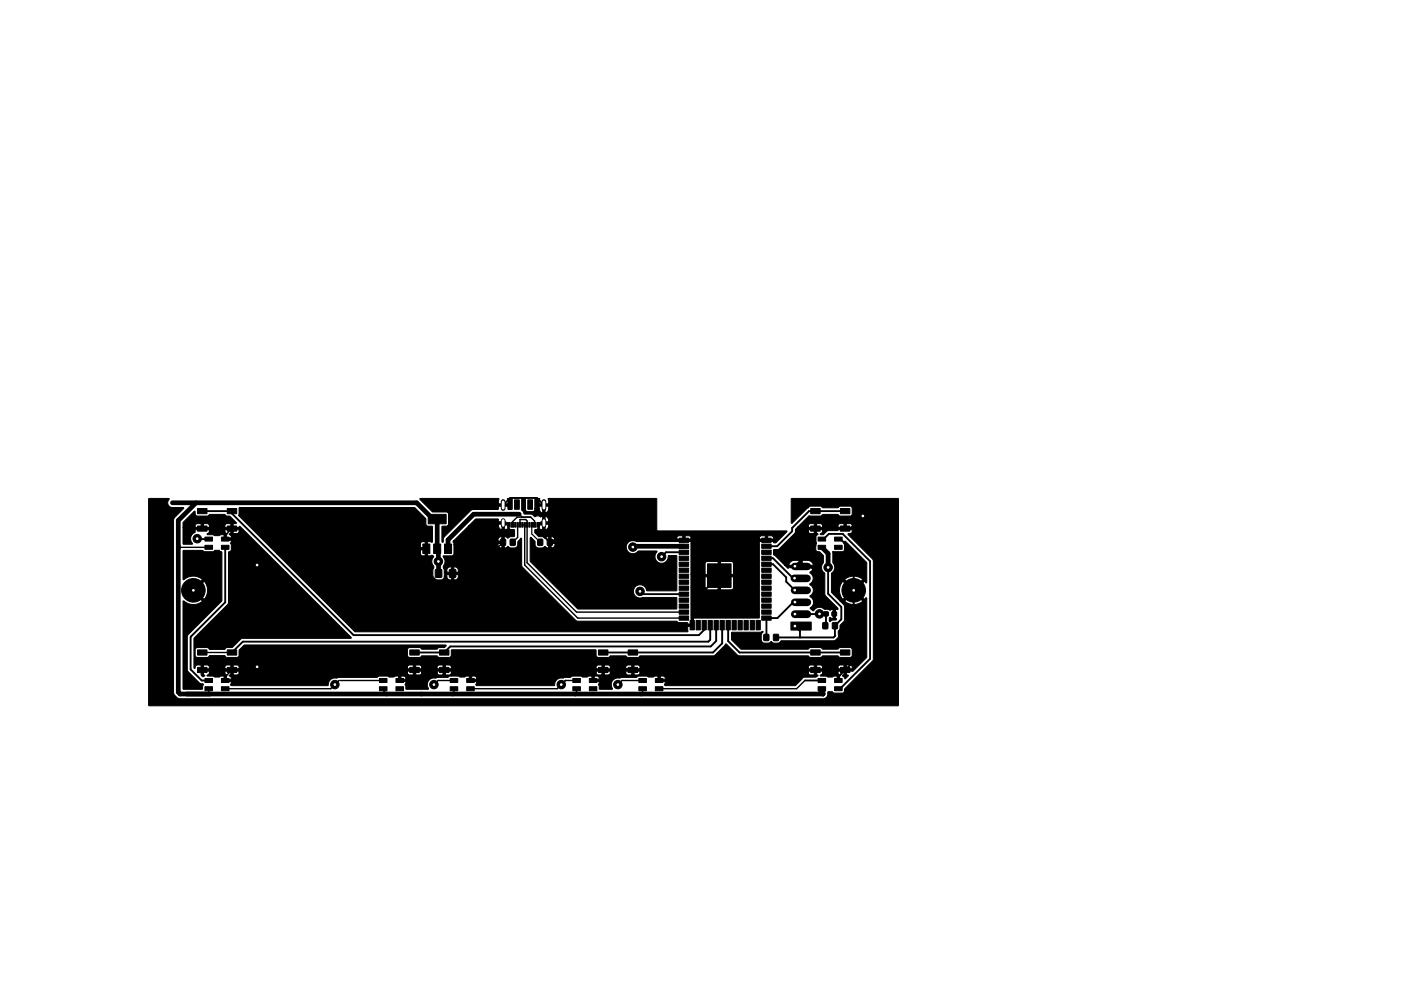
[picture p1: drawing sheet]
<svg xmlns="http://www.w3.org/2000/svg" width="297mm" height="210mm" viewBox="0 0 297 210" stroke-linecap="round" stroke-linejoin="round" font-family="sans-serif">
<g fill="#000" stroke="#000" stroke-width=".21">
<path d="M31.5 105.8l4.3-.1 .1 .2a1.03 1.03 0 0 0-.3 1.1 1.03 1.03 0 0 0 .9 .7h2.3l.2 .1-2 2-.2 .7v36.4l.3 .7 .5 .5 .5 .1h136.6l.7-.4 .2-1 .8-.1 .5 .3h1.7l.3-.1 .2-.7 6-6.2 .1-21-.2-.4-5.2-5.2v-.2l.8-.1 .1-.7h-3l-.1 .2h-2l-1 .8h-.6l-.1-.1 .4-.3 .1-.6h-1.2l-.1 .8 .3 .2-.4 .4v1.1l.1 .3-.1 .4v1.1l.2 .3 .6 .1 .8 .8v1.5l-.2 .2a1.42 1.42 0 0 0 .5 2v4.5l2.8 3-.1 .2h-.5v1.9l.3 .2-1.5 .5v-.9l.7 .2v-1.9l-.6 .2-.4-.2-.9-.1a1.47 1.47 0 0 0-2.3 .4l-.6-.6a1.41 1.41 0 0 0 .2-2.2l-.3-.3a1.44 1.44 0 0 0 0-2.5 1.45 1.45 0 0 0 0-2.5l.5-.5 .3-.6h-5.3l-.2 .2-.6-.7h6.1a1.25 1.25 0 0 0-1.2-1h-1.2v1h-.5v-1h-1.2l-.8 .3-.4 .7h-.8l-2.4-2.2v-1.1l1.2-.2 3.3-3.2 .2-.5h2.7l.4 .5h.8v-.8h-1.2v.3h-2.7v-.4l.4-.4h11.6l-.1-.6-.4-.2h-.8v.8h-.5v-.8l-1 .1-.2 .3v.4h-3.3l-.1-.6-.4-.2h-.8v.8h-.5v-.8l-1 .1-.2 .3v.4h-2.3l2.5-2.5 2.3 .1 .5-.4h3.2l.5 .4h2.2l.4-.4v-1.3l-.5-.4h-2.1l-.5 .3h-3.1l-.5-.3h-2.2l-.7 .5-3.3 3.1v-5.2h22.7l-.1 43.9h-158.8l-.1-.1zM41.2 108.5l.2 .1v.6l.4 .3h2.2l.4-.4h3.2l.5 .4h.6l1.4 1.4-.1 .2h-.6v.8h1.3v-.2h.2l23.6 23.6-.1 .1h-23l-.4 .2-1.7 1.8h-1.2l-.5 .4h-3.1l-.6-.4h-2.3l-.2 .4v1.2l.4 .5h2.2l.5-.4h3.1l.5 .4h2.2l.4-.4v-1.2l1.1-1.1 42.8 .1-.4 .5h-1.1l-.5 .3h-3.1l-.5-.3h-2.2l-.4 .4v1.2l.1 .3 .3 .2h2.2l.5-.4h3.1l.5 .4h2.2l.4-.4v-1.1l.1-.1h30.5l.1 .1v1.1l.4 .4h2.2l.5-.4h3.1l.5 .4h2.2l.5-.4h15.4l.4-.1 2.3-2.4 2.4 2.4 .5 .1h14.5l.5 .4h2.1l.5-.4h3.2l.5 .4h2.1l.5-.4v-1.3l-.5-.4h-2.1l-.5 .3h-3.1l-.6-.3h-2.1l-.5 .3h-14.2l-2-2 .1-1.5 6.2-.1a.18 .18 0 0 1 .2-.2 .18 .18 0 0 1 .2 .1 .18 .18 0 0 1-.1 .2l-.3 .4v1.3l.2 .3 .4 .2h1l.5-.3 .5 .3h1l.6-.5h11.3l.8-.7v-1.3l.4-.5v-.8l1-1v-3l-1-1h1a2.97 2.97 0 0 0 3.8-.1l-1.9-1.9-1.9 2h-1l-1.8-1.9v-.5h1.7l.1 1 .6 1 1.9-2-1.9-1.9-.5 .8-.2 1.1h-1.7v-2.3h2.8l1.9 2 1.9-2a2.98 2.98 0 0 0-3.8 0h-2.8v-1.2l.2-.2a1.45 1.45 0 0 0 .1-2.1v-2.1a.21 .21 0 0 1 0-.3 .21 .21 0 0 1 .3 0h1.9l.2-.3v-1.1a.45 .45 0 0 1 .2-.8l4.6 4.6-.1 4.2h-.1l-.3-.3-1.9 1.9 1.9 2 .3-.4 .2 .1v12.5l-2.9 3h-1.5v.8l.5 .2-.6 .6h-.2l-.5-.7 .3-.1v-.8h-1.2v.5l.4 .4-.1 .2v1.1h-.4l-.1-.1v-1.1h-.7l-.3 .2-2.5-.2-.1-.1 .4-.3 .1-.6h-1.2l-.1 .8h.3v.2l-.4 .3h-2.7l-1.7 1.8h-27.5l-.2-.2 .2-.7h-1.5l-.1-.1v-.4h1.6l-.1-.4-.3-.3h-.7v.7h-.5v-.7h-.7l-.3 .2h-1l-.4-.2h-1.7l-.5 .3h-3.1l-.3 .2a1.49 1.49 0 0 0-1.9 1.5l.2 .8h-2.7l-.2-.9 .2-.7h-1.5l-.1-.1v-.4h1.6l-.1-.4-.3-.3h-.7v.7h-.5v-.7h-.7l-.3 .2h-1l-.4-.2h-1.7l-.4 .3-1.5 .2a1.56 1.56 0 0 0-2 1.6h-16.4l-.2-.2 .2-.7h-1.5l-.1-.1v-.4h1.6l-.1-.4-.3-.3h-.7v.7h-.5v-.7h-.7l-.3 .2h-1l-.4-.2h-1.7l-.5 .3h-2.1l-.3 .2a1.49 1.49 0 0 0-1.9 1.3l.2 1h-4.7l-.2-.9 .2-.7h-1.5l-.1-.1v-.4h1.6l-.1-.4-.4-.3h-.6v.7h-.5v-.7h-.7l-.3 .2h-1l-.4-.2h-1.7l-.5 .3h-8l-.4 .2a1.56 1.56 0 0 0-2 1.6h-20.4l-.2-.2 .2-.7h-1.6v-1.2l-2 .2-.3-.1-1.2-.1-.1-.1 .5-.6h3.3l.4 .6-.1 .2v.6h1v-.4l-.4-.3 .1-.2h1.6l.4-.5h35.7l.1 .4 .3 .1h2.2l.4-.5h3.3l.1 .4 .3 .1h2.2l.4-.5h30.7l.1 .4 .3 .1h2.2l.4-.5h3.3l.1 .4 .3 .1h2.2l.4-.5h35.7l.2 .5h1v-.8h-1.2v.3h-35.7v-.3h-1.2l-.1 .8h-.5v-.8h-1.2v.3h-3.3v-.3h-1.2l-.1 .8h-.5v-.8h-1.2v.3h-30.7v-.3h-1.2l-.1 .8h-.5v-.8h-1.2v.3h-3.3v-.3h-1.2l-.1 .8h-.5v-.8h-1.2v.3h-35.7v-.3h-1.2l-.1 .8h-.5v-.8h-1.2v.3h-3.3v-.3h-1.2l-.1 .8 .3 .2-.4 .2-.4-.4v-1.3h138.1v-.3l-.3-.5h-.9l-.1 .8h-.5v-.8h-.8l-.4 .2v.6h-3.3v-.4l-.3-.3-.9-.1-.1 .8h-.5v-.8h-.8l-.4 .2v.6h-35.7v-.4l-.3-.3-.9-.1-.1 .8h-.5v-.8h-.8l-.4 .2v.6h-3.3v-.4l-.3-.3-.9-.1-.1 .8h-.5v-.8h-.8l-.4 .2v.6h-30.7v-.4l-.3-.3-.9-.1-.1 .8h-.5v-.8h-.8l-.4 .2v.6h-3.3v-.4l-.3-.3-.9-.1-.1 .8h-.5v-.8h-.8l-.4 .2v.6h-35.7v-.4l-.3-.3-.9-.1-.1 .8h-.5v-.8h-.8l-.4 .2v.6h-3.3v-.4l-.3-.3-.9-.1-.1 .8h-.5v-.8h-.8l-.3 .1-.3 .6-.1-.1v-6.3l7.2-7.1 .2-.5v-10.6l.5-.5v-1.1l-.1-.3 .2-.7h-1.5l-.1-1.2-2 .2-.3-.1-1.2-.1-.1-.1 .5-.6h3.3l.4 .6-.1 .2v.6h1v-.4l-.4-.4 1.8-.1 .3-.4v-.4h-1.3v.8h-.5v-.8h-1.2v.3h-3.3v-.3h-3v.6a1.45 1.45 0 0 0-1 1.3l.4 1.2-2-.1v-3.5h10.1v-.8l-1 .1-.2 .3v.4h-3.3l-.1-.6-.4-.2h-.8v.8h-.5v-.8l-1 .1-.2 .3v.4h-2.6v-1.1zM41.9 107.9h2v1.1h-2zM41.9 111.6h2v1.1h-2zM43.5 113.9h1.5v.9h-1.5zM43.5 115.7h1.5v.8h-1.5zM38.8 116.8h4.1l.4 .2h1.8l.4-.2 .9-.1 .6 .5v10.3l-7.1 7.2-.2 .4v7.1l2.6 2.7 .8 .3-.3 1h-3.9l-.1-.1 .1-18.6a3.1 3.1 0 0 0 4 0l-2.2-2.3h.7l1.9 2a2.98 2.98 0 0 0 0-3.9l-1.9 1.9h-.7l2.2-2.2a3.1 3.1 0 0 0-4 0zM48.2 107.9h2v1.1h-2zM48.2 111.6h2v1.1h-2zM47 115.7h1.6v.8h-1.6zM47 113.9h1.6v.9h-1.6zM89.6 115.4h1.5v2h-1.5z"/>
<path d="M91.9 115.4h1.5v2h-1.5zM90.8 109.1h3.8v2h-3.8zM94.2 115.4h1.5v2h-1.5zM89.1 105.8l16.6-.1 .1 .2-.1 1h2l-.1-1.1 .9-.1 .1 .2v2.1l-.1 .1h-.8v-.7h-2l-.2 .7-5.5 .1-5.8 5.7-.3 1.2-.2-.2v-3.1l.1-.2h.9l.3-.2v-2.5l-.4-.3h-2.9l-2.7-2.6zM106.2 114.4h1v1.3h-1zM107.6 110.8h.6v1h-.6zM108.4 110.8h.5v1h-.5zM108.2 114.4h1v1.3h-1zM109.1 110.8h.3v1h-.3zM109.6 110.8h.3v1h-.3zM109.1 106h1v2h-1zM110.1 110.8h.3v1h-.3z"/>
<path d="M110.6 110.8h.3v1h-.3zM50.7 107.7h37.2l2.4 2.3 .1 1.5 1.3 .2v3.2l-.1 .2-1-.2v3l.9-.1 .4 .2-.4 1.1 .1 .4 .4 .7-.2 .8v1.6l.7 .4h1.3l.4-.7h.5l.2 .5 .4 .2h1.3l.4-.2 .2-.9h-1v1.1h-.5v-1.1h-.9l-.1 .4h-.5v-.9h3v-.5l-.3-.5-.7-.1v1.1h-.5v-1.1h-.5l-.3 .3-.2 .8h-.5l-.2-1.4a1.46 1.46 0 0 0-.1-1.9l.2-.2h1.7l.3-.1 .1-.3v-1.9h9.4a.75 .75 0 0 0 .8 .7v-1h-.8v.3h-9.4l-.2-.7 .2-.1h10.2v-.9a.75 .75 0 0 0-.8 .7v.2h-9.4l3.2-3.3h6.3a.96 .96 0 0 0 .7 .9v-1.2h-.7v.3h-6.3l1.5-1.4h4.7l.1 .6h1.4l.4 .3v.2h-.6v1.2l.4-.1 .3 .1 .2-.5 .4 .5h.8l.1 1.3-.1 .2h-.9l-.4 .3-.8-.3v2.4l.8-.4 .5 .3h1.2l.3-.4 .1-.9 .7-.7 .1 5.7 .1 .4 11.6 11.5h21.2l.4 .3h1.8l.1 .3h.7v-7.7h3l.1 .3 .4 .1h5.1l.4-.2v-2.5h-2.7v2.7h-.6v-2.7h-2.7v2.3h-3v-2.8h9v-2.4l-.5-.4h-2.2v2.8h-.6v-2.8h-2.3l-.3 .2-.1 .3v2.3h-3v-7h-11.5a1.43 1.43 0 0 0-2 .4 1.43 1.43 0 0 0 .4 2 1.43 1.43 0 0 0 2-.4h3.9l-.3 .5a1.43 1.43 0 0 0 1.1 2.1 1.43 1.43 0 0 0 1.6-1.6h1.8v7.4l-6.3 .1-.5-1a1.41 1.41 0 0 0-2.4 .9 1.41 1.41 0 0 0 2 1.5h7.1l.1 2.4h-21l-10.1-10.1 .1-5.1 .9 .8 .1 1 .4 .4h1.1l.6-.3 .5 .4 .7-.1a.72 .72 0 0 0 .9-.6v-.3h-.9v.9h-.5v-1.4h1.4l-.1-.4h46.4v-.3l-.4-.4h-.8v.7h-.6v-.7h-.7l-.4 .2-.1 .5h-14.5v-.5l-.2-.2h-1v.7h-.6v-.7h-.7l-.4 .2-.1 .5h-25.9l-.2-.4-.5-.2-.1 1h-.5v-.9l-.8 .3-.5-.3h-.7l-.9-.9v-.6h.4l.4-.5 .2 .1v.4l.3-.1 .3 .1h.7l.6-.5v-.7h-.7v1.2h-.5v-1.2h-.7l-.1-.2 .4-.3h1.6v-.4l-.3-.5-.4-.3v1.2h-.5v-1.2l-.6 .1a.82 .82 0 0 0-1 0l-.8-.5-1.6-.1-.5-.8v-2.4h.8v2.3l.3 .4h1.3l.3-.2 .1-.4h.9a.96 .96 0 0 0 .8 1h.5a.95 .95 0 0 0 .7-.9v-.6h-.7v1.5h-.5v-1.5h-.8v.5h-.9v-2.1h1l-.1 1.1h2l-.1-1 .1-.2h22.8l.1 .2v6.7h27.5l.2 .2-2.4 2.4h-.4l-.1-.3h-3l-.1 16.2h-13.9v1.7l-1.2 .1 .1 1-.2 .1h-70.4l-16.6-16.5h30.4l.3 .4h.7v-1.2h-1v.8h-30.4l-1.3-1.3h32.7v-1.3l-.8 .2-.2 1.1h-31.7l-6.8-6.8zM111.1 110.8h.3v1h-.3zM111.6 110.8h.3v1h-.3zM112.1 110.8h.3v1h-.3zM112.6 110.8h.3v1h-.3zM111.9 106h1v2h-1zM113.1 110.8h.5v1h-.5zM114 114.4h1v1.3h-1zM113.8 110.8h.6v1h-.6zM116.1 114.4h1v1.3h-1zM144 114.2h2v.9h-2z"/>
<path d="M144 115.4h2v.9h-2zM144 116.7h2v.9h-2zM144 118h2v.9h-2zM161.5 118h2v.9h-2zM161.5 116.7h2v.9h-2zM161.5 115.4h2v.9h-2zM161.5 114.2h2v.9h-2zM171.9 107.9h2v1.1h-2zM171.9 111.6h2v1.1h-2zM173.4 113.9h1.6v.9h-1.6zM173.4 115.7h1.6v.8h-1.6zM178.2 107.9h2v1.1h-2z"/>
<path d="M178.2 111.6h2v1.1h-2zM177 115.7h1.6v.8h-1.6zM177 113.9h1.6v.9h-1.6zM41.9 137.9h2v1.1h-2zM48.2 137.9h2v1.1h-2zM86.9 137.9h2v1.1h-2zM92.3 120.9h1.3v1.6h-1.3zM93.2 137.9h2v1.1h-2zM95.3 120.9h1.3v1.6h-1.3zM126.9 137.9h2v1.1h-2zM133.2 137.9h2v1.1h-2zM144 119.3h2v.9h-2z"/>
<path d="M144 120.5h2v.9h-2zM144 121.8h2v.9h-2zM144 123.1h2v.9h-2zM144 124.3h2v.9h-2zM144 125.6h2v.9h-2zM144 126.9h2v.9h-2zM144 128.1h2v.9h-2zM144 129.4h2v.9h-2zM144 130.7h2v.9h-2zM146.3 131.6h.9v2h-.9zM147.6 131.6h.9v2h-.9zM148.9 131.6h.9v2h-.9z"/>
<path d="M150 119.6h5v5h-5zM150.1 131.6h.9v2h-.9zM151.4 131.6h.9v2h-.9zM152.7 131.6h.9v2h-.9zM153.9 131.6h.9v2h-.9zM155.2 131.6h.9v2h-.9zM156.5 131.6h.9v2h-.9zM157.7 131.6h.9v2h-.9zM159 131.6h.9v2h-.9zM160.3 131.6h.9v2h-.9zM161.5 130.7h2v.9h-2zM161.5 129.4h2v.9h-2z"/>
<path d="M161.5 128.1h2v.9h-2zM161.5 126.9h2v.9h-2zM161.5 125.6h2v.9h-2zM161.5 124.3h2v.9h-2zM161.5 123.1h2v.9h-2zM161.5 121.8h2v.9h-2zM161.5 120.5h2v.9h-2zM161.5 119.3h2v.9h-2zM162 134.6h1v1.3h-1zM164 134.6h1v1.3h-1zM171.9 137.9h2v1.1h-2zM167.7 132h4.3v1.7h-4.3z"/>
<path d="M174.7 129.8h.9v.9h-.9zM174.5 132.1h1v1.3h-1zM176.4 129.8h.9v.9h-.9zM176.5 132.1h1v1.3h-1zM178.2 137.9h2v1.1h-2zM41.9 141.6h2v1.1h-2zM43.5 143.9h1.5v.9h-1.5zM43.5 145.7h1.5v.8h-1.5zM48.2 141.6h2v1.1h-2zM47 145.7h1.6v.8h-1.6zM47 143.9h1.6v.9h-1.6zM80.4 145.7h1.6v.8h-1.6z"/>
<path d="M80.4 143.9h1.6v.9h-1.6zM84 143.9h1.5v.9h-1.5zM84 145.7h1.5v.8h-1.5zM86.9 141.6h2v1.1h-2zM93.2 141.6h2v1.1h-2zM95.4 143.9h1.7v.9h-1.7zM95.4 145.7h1.7v.8h-1.7zM99 145.7h1.5v.8h-1.5zM99 143.9h1.5v.9h-1.5zM121.5 143.9h1.6v.9h-1.6zM121.5 145.7h1.6v.8h-1.6zM124.9 145.7h1.6v.8h-1.6z"/>
<path d="M124.9 143.9h1.6v.9h-1.6zM126.9 141.6h2v1.1h-2zM133.2 141.6h2v1.1h-2zM135.5 143.9h1.6v.9h-1.6zM135.5 145.7h1.6v.8h-1.6zM138.9 145.7h1.6v.8h-1.6zM138.9 143.9h1.6v.9h-1.6zM171.9 141.6h2v1.1h-2zM173.4 143.9h1.6v.9h-1.6zM173.4 145.7h1.6v.8h-1.6zM178.2 141.6h2v1.1h-2zM177 145.7h1.6v.8h-1.6z"/>
<path d="M177 143.9h1.6v.9h-1.6z"/>
<circle cx="41.8" cy="114.3" r=".9"/>
<circle cx="54.5" cy="119.9" r=".9"/>
<circle cx="92.9" cy="119.1" r=".9"/>
<circle cx="134.2" cy="116.1" r=".9"/>
<circle cx="140.3" cy="118.1" r=".9"/>
<circle cx="182.9" cy="109.5" r=".9"/>
<circle cx="41" cy="125.2" r="2.5"/>
<circle cx="135.7" cy="125.5" r=".9"/>
<circle cx="173.8" cy="130.2" r=".9"/>
<circle cx="175.6" cy="120.4" r=".9"/>
<circle cx="181" cy="125.2" r="2.5"/>
<circle cx="54.5" cy="141.5" r=".9"/>
<circle cx="71" cy="145.2" r=".9"/>
<circle cx="92" cy="145.2" r=".9"/>
<circle cx="119" cy="145.2" r=".9"/>
<circle cx="131" cy="145.2" r=".9"/>
</g>
<path d="M168.5 130.3h2.7" fill="none" stroke="#000" stroke-width="1.7"/>
<path d="M168.4 122.7h2.7M168.5 125.2h2.6M168.5 120.2h2.7M168.5 127.8h2.7" fill="none" stroke="#000" stroke-width="1.6"/>
<path d="M36.6 106.7h51.7l3.5 3.4h.9v6.3l.2 .3 .1 5M41.6 106.7l-3.8 3.7v36.5l.4 .3h136.3M92.9 119.1l.1 .1M106.7 106.4v1.5M106.7 110.4v1M110.1 109.1h-9.7l-5.4 5.4v1.9M115.3 106.4v1.5M115.3 110.5v1M145 115.9h-10.7l-.1 .2M174.3 116.1l1.3 1.4v2.9M174 146.7l.5 .5M174.3 146.1l.2 .3v.8" fill="none" stroke="#000" stroke-width="1"/>
<g fill="none" stroke="#000" stroke-width=".3">
<path d="M37.8 115.7l.4 .4h6.1M42.9 112.1h6.3M49.2 112.1v2.5l5.3 5.3M49.2 112.1l-1.5 1.5v.8M107.9 111.3h-.8l-.4-.4v4.1l-6.6 6.7h-4.1M108.7 111.3v-.6l.9-1h2.9l.9 .8v.8M109.8 111.3v2.7l-1.1 1.1M110.1 109.1l.6 .6M110.2 111.3l.1-1.1h1.2l.3 .3v8.9l10.4 10.5h22.8M110.8 111.3h.4v8.6l11.3 11.2h22.5M114.3 115.1h.2M115.3 111l-.4 .3h-.8"/>
<path d="M42.9 138.4h6.3M44.3 146.1v.9l.2 .2M49.2 142.1l-1.5 1.5v.8M54.5 141.5l-.7 .6h-10.9M71.9 144.4l-1.8 1.7h-22.4M72.1 144.4h9.2M81.3 146.1v.4l.7 .7M96.2 144.4h-3.3l-.9 .8M96.2 146.1v.9l-.2 .2M122.2 144.4h-2.3l-1.8 1.7h-18.3M122.2 146.1v.9l-.2 .2M136.2 144.4h-4.3l-.9 .8"/>
<path d="M136.2 146.1v.9l-.2 .2M170.6 144.4l-1.7 1.7h-29.1"/>
</g>
<g fill="none" stroke="#000" stroke-width=".4">
<path d="M41.8 114.3l2.5 .1M42.9 108.4h6.3v.6l25.8 25.7h73.2l1.1-1.1v-1M47.7 116.1v11.7l-7.3 7.3v6.9l2.4 2.4h1.5M90.4 116.4v4.7l3.1 3.1h1.9l.6-.5v-2M106.7 107.1l1.5-1.5h5.6l1.5 1.5v6.7l1.3 1.3 .4-.5h45.5M145 117.2h-3.8l-.9 .9M152.3 114.6l.2 .2v7.3l-5.7 5.8v4.7M162.5 114.6h.1M162.5 119.7h1.4l2.8 2.8v.9l1.8 1.8M162.5 118.4h1.4l4.2 4.3h.4M174.3 114.4h.3l1.1-1.1h3l5.8 5.8v20.7l-6.4 6.3h-.4M175.6 117.5v8.5l2.8 2.8v2.6l-1.4 1.3 .1 2.2-.4 .3h-12.2"/>
<path d="M177.7 114.4h.5l2.8 2.8v23.1l-3.3 3.3v.8M179.2 108.4h-7.7l-3.5 3.6v.7l-3.2 3.2h-2.3M182.9 109.5l-2.6 2.6h-7.4v3.7l-4.4 4.3h3.3l1.7 1.8v3.8l3.4 3.4v1.1M135.7 125.5l.6 .6h8.7M150.6 132.6v3.1l-.4 .4h-98.7l-2.3 2.3M151.8 132.6v3.4l-1.1 1.2h-55.2l-1.3 1.2h-6.3M153.1 132.6v3.9l-1.9 1.9h-23.3M154.4 132.6v3.4l2.4 2.4h22.4M168.5 132.8l1.1 1.1v1.3M168.5 130.3l6.6-.1v2.4l-.1 .1M168.5 127.7h-.3l-3.4 3.4h-2.3v4.1M44.2 142.1h50"/>
<path d="M89.3 147.2h.1M130.4 147.2h44.1M170.6 144.4h3.7M172.9 142.1h6.3"/>
</g>
<path d="M112.8 111.3v2l1.7 1.8" fill="none" stroke="#000" stroke-width=".25"/>
<g fill="#fff" stroke="#fff" stroke-width=".21">
<circle cx="119" cy="145.2" r=".17"/>
<circle cx="131" cy="145.2" r=".17"/>
<circle cx="92" cy="145.2" r=".17"/>
<circle cx="71" cy="145.2" r=".17"/>
<circle cx="182.9" cy="109.5" r=".17"/>
<circle cx="54.5" cy="119.9" r=".17"/>
<circle cx="54.5" cy="141.5" r=".17"/>
<circle cx="41.8" cy="114.3" r=".17"/>
<circle cx="135.7" cy="125.5" r=".17"/>
<circle cx="175.6" cy="120.4" r=".17"/>
<circle cx="140.3" cy="118.1" r=".17"/>
<circle cx="173.8" cy="130.2" r=".17"/>
<circle cx="134.2" cy="116.1" r=".17"/>
<circle cx="92.9" cy="119.1" r=".17"/>
<circle cx="181" cy="125.2" r=".18"/>
<circle cx="168.5" cy="132.8" r=".17"/>
<circle cx="168.5" cy="130.3" r=".17"/>
<circle cx="168.5" cy="127.7" r=".17"/>
<circle cx="168.5" cy="125.2" r=".17"/>
<circle cx="168.5" cy="122.7" r=".17"/>
<circle cx="168.5" cy="120.1" r=".17"/>
<circle cx="41" cy="125.2" r=".17"/>
<circle cx="114" cy="110.2" r=".17"/>
</g>
<path d="M106.7 106.5v1.3M106.7 110.4v1M107.9 110.2h.2M115.3 106.5v1.3M115.3 110.5v1" fill="none" stroke="#fff" stroke-width=".6"/>
</svg>
